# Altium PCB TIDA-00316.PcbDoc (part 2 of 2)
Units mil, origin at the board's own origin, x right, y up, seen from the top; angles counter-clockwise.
Board outline 3345 x 4425 mil, 4 copper layers (Top Layer, L1_GND, L2_POWER, Bottom Layer), stack 90 mil thick; 218 components, 101 nets, 687 pads, 221 vias.

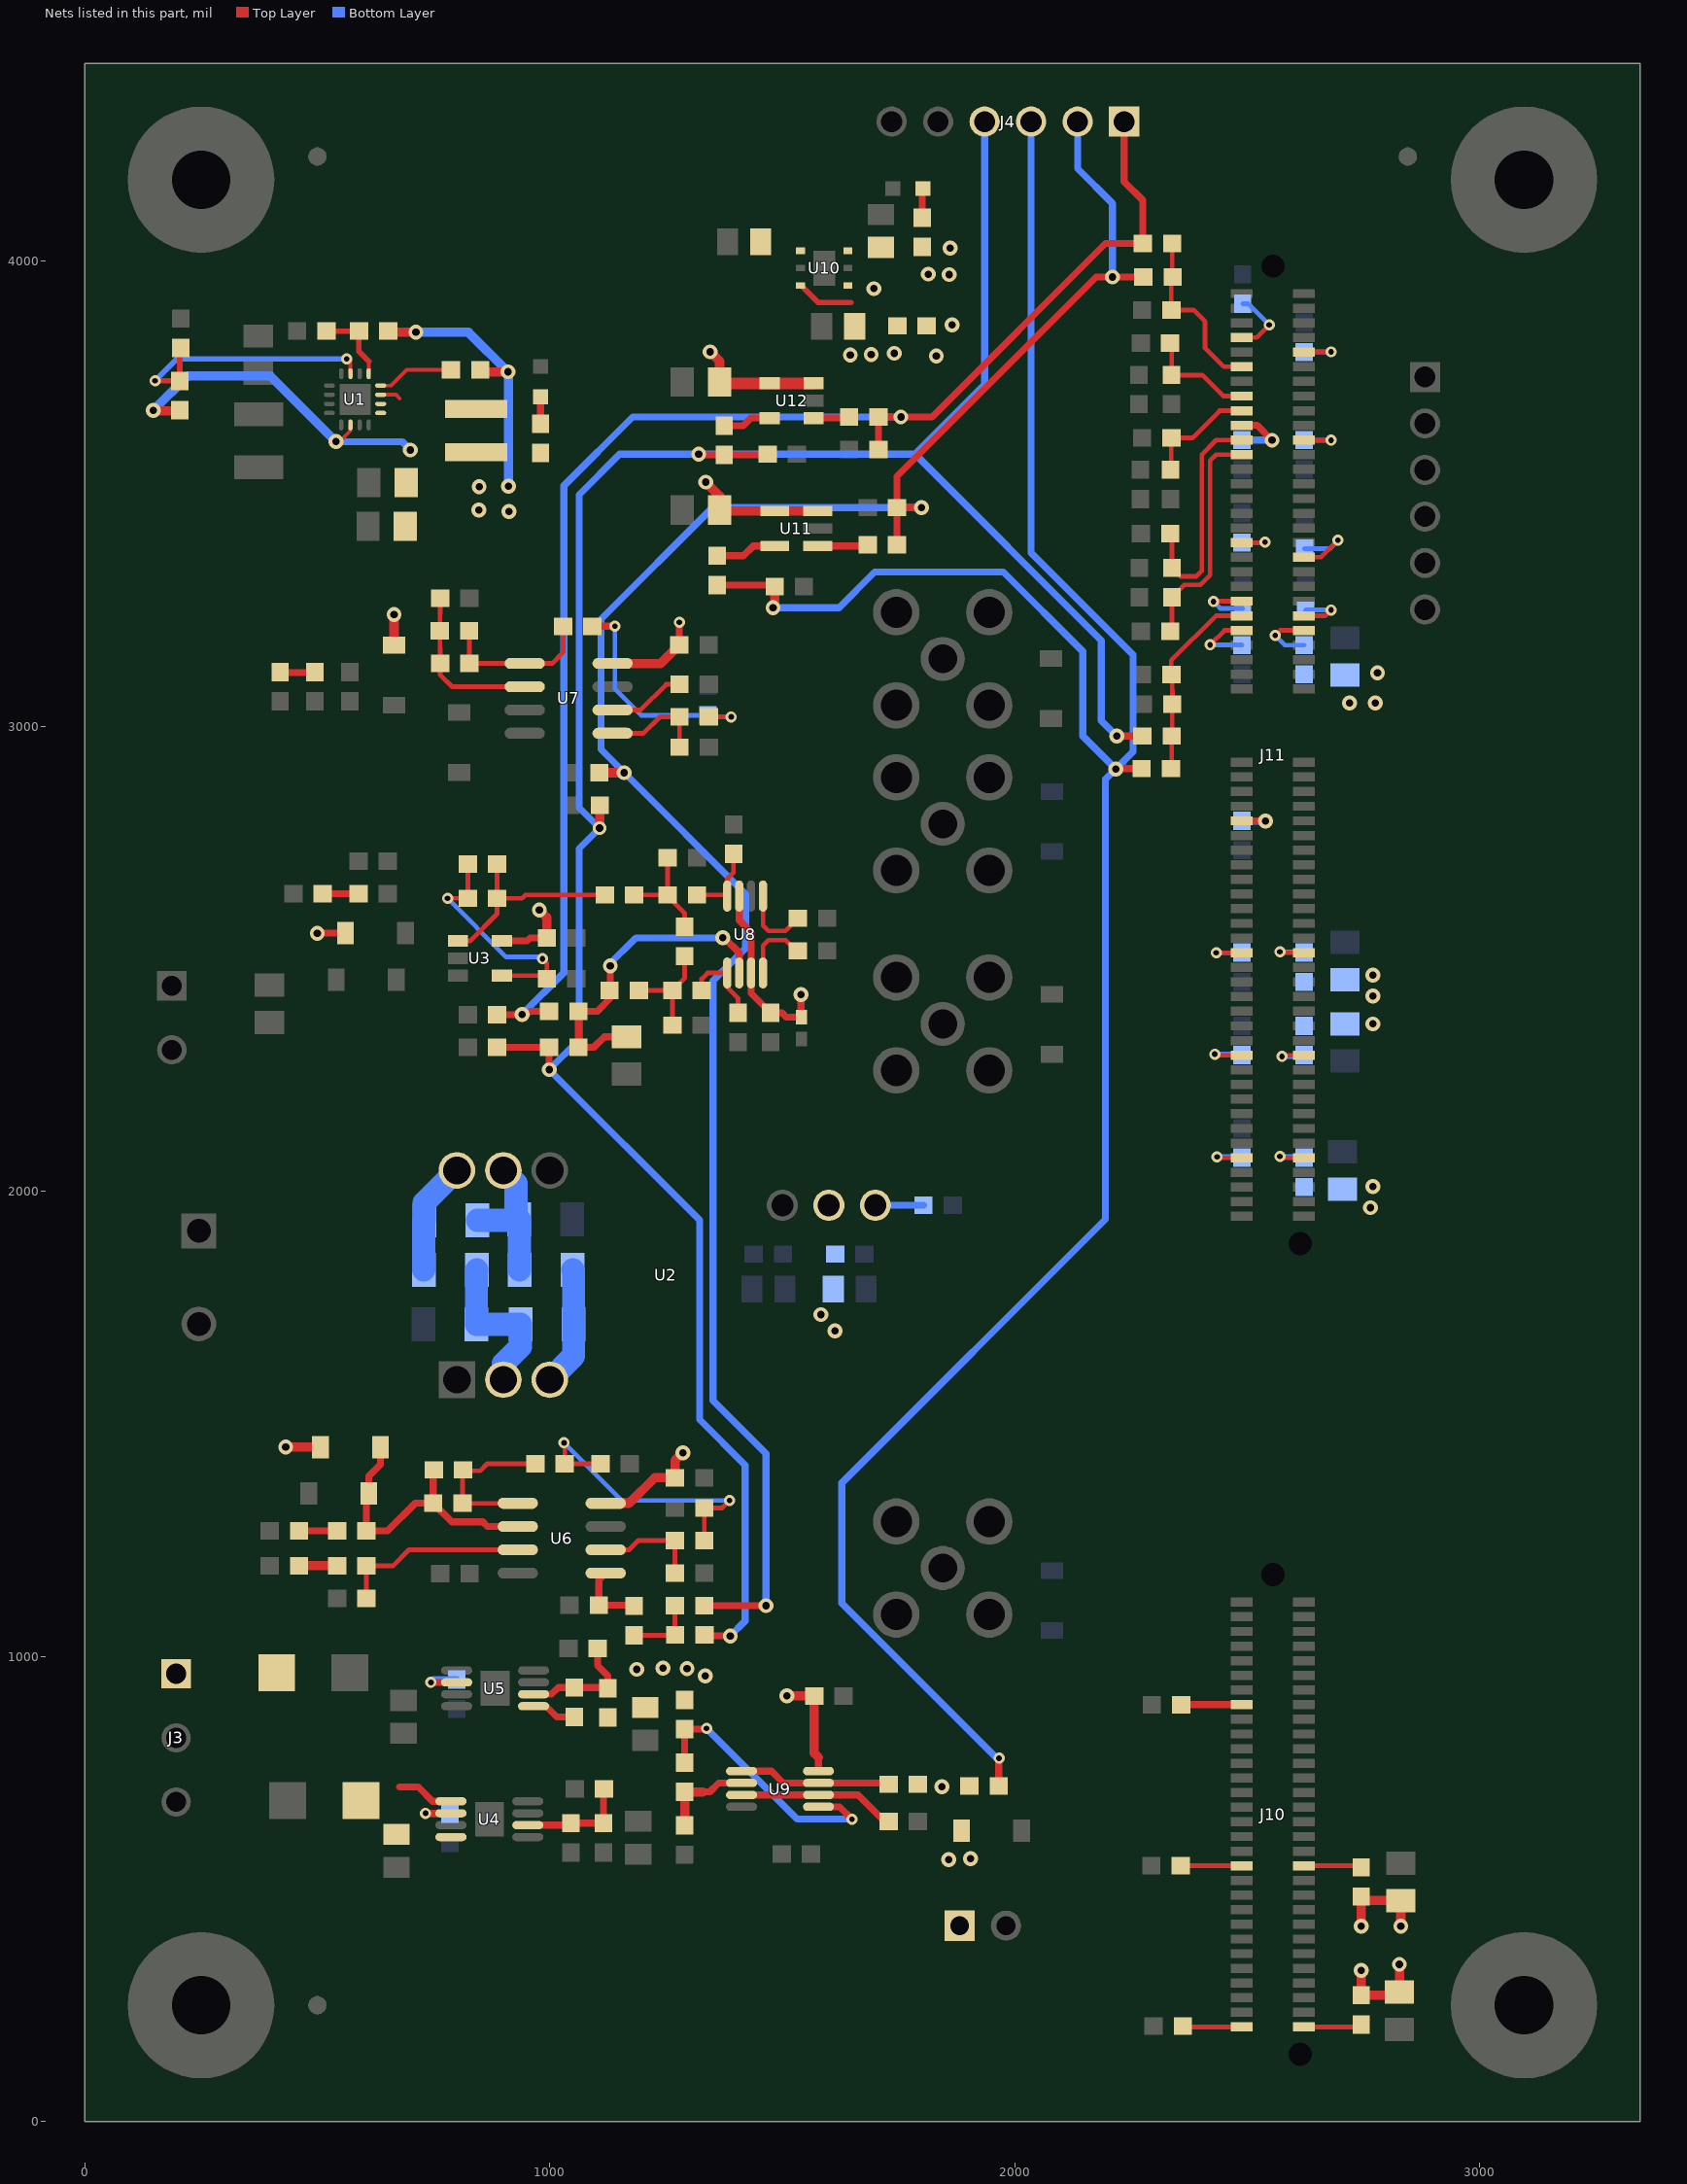
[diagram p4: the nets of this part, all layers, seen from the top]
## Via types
v1: diameter 32, hole 16, Top Layer to Bottom Layer, 160 vias
v2: diameter 24, hole 12, Top Layer to Bottom Layer, 40 vias
v3: diameter 19.68, hole 7.87, Top Layer to Bottom Layer, 16 vias
v4: diameter 30, hole 16, Top Layer to Bottom Layer, 5 vias

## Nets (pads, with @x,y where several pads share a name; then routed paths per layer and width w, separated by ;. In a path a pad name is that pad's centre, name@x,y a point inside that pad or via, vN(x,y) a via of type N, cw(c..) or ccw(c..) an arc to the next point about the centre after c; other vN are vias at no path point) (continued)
NetC5_1: C5.1 R16.1 R22.1 U6.1 | length 352.2
  Top Layer w10: U6.1@931.08,1329.22 R16.1@812.06,1329.22 812.06,1399.22 850.57,1399.22 865.57,1414.22 R22.1@969.07,1414.22
NetC5_2: C5.2 D1.1 D2.2 R10.2 R16.2 U6.2 | length 635
  Top Layer w15: D2.2@635.47,1450 635.47,1412.47 610.47,1387.47 D1.1@610.47,1350 605.5,1345.03 R10.2@605.5,1270 651,1270 710.22,1329.22 R16.2@749.07,1329.22 ; C5.2@749.07,1401 R16.2@749.07,1329.22 ; U6.2@931.08,1279.22 865.57,1279.22 855.57,1289.22 789.07,1289.22 R16.2@749.07,1329.22
NetC6_1: C6.1 D4.2 U4.5 U4.8 | length 123
  Top Layer w15: 677,719 717,719 747.61,688.39 U4.5@787.32,688.39
NetC10_1: C10.1 R18.1 R26.1 U7.1 | length 337.8
  Top Layer w10: C10.1@826.93,3205 R18.1@826.93,3135 U7.1@945.94,3135 1005,3135 1028.5,3158.5 R26.1@1028.5,3215
NetC10_2: C10.2 R17.2 R18.2 U7.2 | length 356.7
  Top Layer w10: R17.2@763.94,3275 C10.2@763.5,3205 R18.2@763.94,3135 763.94,3111.06 790,3085 U7.2@945.94,3085
NetC11_1: C11.1 R19.1 R31.1 U3.1 | length 450.6
  Top Layer w10: U3.1@802.4,2538.4 828.4,2538.4 886.5,2596.5 R19.1@886.5,2630 ; C11.1@886.5,2704 R19.1@886.5,2630 ; R31.1@1118.49,2637.2 947.2,2637.2 940,2630 R19.1@886.5,2630
NetC11_2: C11.2 R19.2 R23.2 U3.4 | length 524.4
  Top Layer w10: v2(780,2630) R19.2@823.5,2630 823.5,2699 818.5,2704 C11.2@818.5,2705 ; U3.4@896.89,2463.6 987.09,2463.6 R23.2@993.49,2457.2 993.49,2490.51 v2(984,2500)
  Bottom Layer w10: v2(780,2630) 906,2504 980,2504 v2(984,2500)
NetC14_1: C14.1 R22.2 R34.1 R35.1 | length 661.1
  Top Layer w10: v2(1030.57,1459.22) 1032.06,1457.72 R22.2@1032.06,1414.22 C14.1@1109.07,1414.22 ; R35.1@1332.06,1249.22 R34.1@1332.06,1319.22 1370.57,1319.22 v2(1386.57,1335.22)
  Bottom Layer w10: v2(1030.57,1459.22) 1154.57,1335.22 v2(1386.57,1335.22)
NetC15_2: C15.2 R28.2 R30.1 U4.2 | length 238.2
  Top Layer w15: U4.2@952.68,637.2 1040.71,637.2 C15.2@1045,641.5 R30.1@1115,641.5 1115,713.5 R28.2@1116.5,715
NetC16_2: C16.2 R29.2 R32.1 U5.2 | length 266.5
  Top Layer w15: U5.2@964.96,918.58 1003.58,918.58 1017.87,932.87 C16.2@1052.28,932.87 1123.62,932.87 R32.1@1118.78,937.72 ; R29.2@1102.78,1017.38 1102.78,980.22 1125,958 R32.1@1125,931.5
NetC19_2: C19.2 R35.2 U6.6 | length 227.3
  Top Layer w10: U6.6@1120.06,1229.22 1170.57,1229.22 1190.57,1249.22 R35.2@1269.07,1249.22 C19.2@1269.07,1179.22
NetC23_1: C23.1 R42.2 U7.5 | length 223.5
  Top Layer w10: U7.5@1134.92,2985 1201.5,2985 1236.5,3020 R42.2@1278.94,3020 C23.1@1278.94,2955
NetC26_1: C26.1 R31.2 R37.1 R38.2 | length 235.6
  Top Layer w10: R31.2@1181.48,2637.2 R38.2@1253.49,2637.2 ; R37.1@1253.49,2717.2 R38.2@1253.49,2637.2 ; C26.1@1289.98,2568.7 1289.98,2597.22 1253.49,2633.71 R38.2@1253.49,2637.2
NetC26_2: C26.2 R33.2 R39.2 R40.1 | length 231.5
  Top Layer w10: R33.2@1191.48,2432.2 R39.2@1263.49,2432.2 ; R40.1@1263.49,2357.2 R39.2@1263.49,2432.2 ; C26.2@1289.98,2505.7 1289.98,2458.7 R39.2@1263.49,2432.2
NetC27_2: C27.2 R38.1 U8.8 | length 162.5
  Top Layer w10: R38.1@1316.48,2637.2 1379.27,2637.2 U8.8@1381.6,2634.88 1381.6,2671.6 1394.98,2684.98 C27.2@1394.98,2725.7
NetC28_2: C28.2 R39.1 U8.1 | length 180.6
  Top Layer w10: R39.1@1326.48,2432.2 1326.48,2456.9 1339.11,2469.52 U8.1@1381.6,2469.52 1381.6,2441.6 1381.6,2438.4 1404.98,2415.02 C28.2@1404.98,2383.7
NetC29_1: C29.1 U10.1
NetC42_1: C42.1 J11.11 R63.2 R64.2 | length 379.4
  Top Layer w10: R63.2@2338.5,4038 2338.5,3966 2336.5,3964 C42.1@2336.5,3895 2384,3895 2409,3870 2409,3813 2449.07,3772.93 J11.11@2488.07,3772.93
NetC43_1: C43.1 C61.1 J11.45 R60.2 R62.2 | length 461.6
  Top Layer w10: R60.2@2335.5,2909 2337.5,2911 R62.2@2337.5,2979 2338.5,2980 C43.1@2338.5,3047 ; 2339,3077 C43.1@2339,3047 ; C43.1@2343,3047 C43.1@2339,3047 ; J11.45@2488.07,3237.5 2432.5,3237.5 2336.5,3141.5 C61.1@2336.5,3111 2338.5,3109 C43.1@2338.5,3047 ; C43.1@2338.5,3047 C43.1@2339,3047 ; C43.1@2338.5,3047 2339,3046.5 C43.1@2339,3047
NetC44_1: C44.1 J11.17 R61.2 | length 244.9
  Top Layer w10: C44.1@2335,3551.5 2336.5,3552.99 R61.2@2336.5,3620 2382,3620 2440.45,3678.44 J11.17@2488.07,3678.44
NetC45_1: C45.1 J11.15 R57.2 | length 239.7
  Top Layer w10: R57.2@2333.7,3824 2337.2,3820.5 C45.1@2337.2,3755.5 2337.7,3755 2403,3755 2448.06,3709.94 J11.15@2488.07,3709.94
NetC46_1: C46.1 J11.21 R58.2 | length 501.2
  Top Layer w10: R58.2@2334.23,3414 2337.73,3410.5 C46.1@2337.73,3340.5 2356.23,3322 2390,3322 2402,3334 2402,3584.45 2433,3615.45 J11.21@2488.07,3615.45
NetC46_2: C46.2 J11.23 R59.2 | length 496.3
  Top Layer w10: R59.2@2334.23,3204 2337.73,3207.5 C46.2@2337.73,3277.5 2364.23,3304 2399,3304 2420,3325 2420,3571 2432.96,3583.96 J11.23@2488.07,3583.96
NetC57_2: C57.2 R26.2 R42.1 | length 506.5
  Top Layer w10: R42.1@1341.93,3020 v2(1390,3020)
  Top Layer w15: R26.2@1091.5,3215 v2(1140,3215)
  Bottom Layer w10: v2(1140,3215) 1140,3079.92 1196.42,3023.5 C57.2@1340,3023.5 1343.5,3020 v2(1390,3020)
NetC58_1: C58.1 U5.6 | length 113.3
  Top Layer w15: v2(744.17,944.17) U5.6@799.61,944.17
  Bottom Layer w15: v2(744.17,944.17) 750.08,950.08 C58.1@799.61,950.08
NetC59_1: C59.1 U4.6 | length 109.9
  Top Layer w15: v2(732.8,662.8) U4.6@787.32,662.8
  Bottom Layer w15: v2(732.8,662.8) 731.5,661.5 C59.1@785,661.5
NetJ10_135: J10.135 R96.2 | length 130.7
  Top Layer w15: R96.2@2357.5,896 2357.72,896.22 J10.135@2488.07,896.22
NetJ10_157: J10.157 R65.2 | length 131.7
  Top Layer w10: R65.2@2356.5,550 2356.73,549.76 J10.157@2488.07,549.76
NetJ10_158: J10.158 R68.1 | length 124.4
  Top Layer w10: J10.158@2621.93,549.76 2741.73,549.76 R68.1@2745,546.5
NetJ10_179: J10.179 R66.2 | length 127.3
  Top Layer w10: R66.2@2361.5,205 2363.19,203.31 J10.179@2488.07,203.31
NetJ10_180: J10.180 R67.1 | length 125.2
  Top Layer w10: J10.180@2621.93,203.31 2739.8,203.31 R67.1@2745,208.5
NetJ11_7: J11.7 R77.1 | length 146
  Top Layer w10: J11.7@2488.07,3835.93 2519.93,3835.93 v2(2547,3863)
  Bottom Layer w10: R77.1@2490,3908.5 2501.5,3908.5 v2(2547,3863)
NetJ11_10: J11.10 R73.2 | length 116.6
  Top Layer w10: J11.10@2621.93,3804.43 2679.43,3804.43 v2(2680,3805)
  Bottom Layer w10: R73.2@2621.93,3804.43 2622.5,3805 v2(2680,3805)
NetJ11_19: J11.19 R97.2 | length 143.3
  Top Layer w15: J11.19@2488.07,3646.95 2521.05,3646.95 v1(2553,3615)
  Bottom Layer w15: R97.2@2488.07,3615.45 2552.55,3615.45 v1(2553,3615)
NetJ11_22: J11.22 R71.2 | length 116.5
  Top Layer w10: J11.22@2621.93,3615.45 2679.55,3615.45 v2(2680,3615)
  Bottom Layer w10: R71.2@2621.93,3615.45 2622.38,3615 v2(2680,3615)
NetJ11_35: J11.35 R81.2 | length 100.7
  Top Layer w10: J11.35@2488.07,3394.98 2536.98,3394.98 v2(2538,3396)
  Bottom Layer w10: R81.2@2488.07,3394.98 2536.98,3394.98 v2(2538,3396)
NetJ11_38: J11.38 R70.2 | length 167.9
  Top Layer w10: J11.38@2621.93,3363.48 2658.48,3363.48 v2(2695,3400)
  Bottom Layer w10: R70.2@2623,3381.5 2676.5,3381.5 v2(2695,3400)
NetJ11_43: J11.43 R78.2 | length 130.5
  Top Layer w10: v2(2427,3268) 2427.99,3268.99 J11.43@2488.07,3268.99
  Bottom Layer w10: v2(2427,3268) 2441.5,3253.5 R78.2@2490,3253.5
NetJ11_46: J11.46 R69.2 | length 118.9
  Top Layer w10: J11.46@2621.93,3237.5 2667.5,3237.5 v2(2680,3250)
  Bottom Layer w10: R69.2@2625,3248.5 2626.5,3250 v2(2680,3250)
NetJ11_47: J11.47 R79.2 | length 149.2
  Top Layer w10: v2(2420,3175) 2451,3206 J11.47@2488.07,3206
  Bottom Layer w10: v2(2420,3175) 2487.58,3175 R79.2@2488.07,3174.51
NetJ11_48: J11.48 R74.1 | length 136.9
  Top Layer w10: v2(2560,3195) 2571,3206 J11.48@2621.93,3206
  Bottom Layer w10: v2(2560,3195) 2580.49,3174.51 R74.1@2621.93,3174.51
NetJ11_65: J11.65 R95.2 | length 101.5
  Top Layer w15: J11.65@2488.07,2796.56 2538.45,2796.56 v1(2539,2796)
  Bottom Layer w15: R95.2@2488.62,2796 v1(2539,2796)
NetJ11_83: J11.83 R80.2 | length 110
  Top Layer w10: v2(2433.09,2513.09) J11.83@2488.07,2513.09
  Bottom Layer w10: v2(2433.09,2513.09) R80.2@2488.07,2513.09
NetJ11_84: J11.84 R75.1 | length 105.4
  Top Layer w10: v2(2570,2515) 2571.91,2513.09 J11.84@2621.93,2513.09
  Bottom Layer w10: v2(2570,2515) 2620.02,2515 R75.1@2621.93,2513.09
NetJ11_97: J11.97 R82.2 | length 118.1
  Top Layer w10: v2(2430,2295) 2432.38,2292.62 J11.97@2488.07,2292.62
  Bottom Layer w10: v2(2430,2295) 2485.69,2295 R82.2@2488.07,2292.62
NetJ11_98: J11.98 R72.1 | length 96.5
  Top Layer w10: v2(2574.77,2290) 2577.38,2292.62 J11.98@2621.93,2292.62
  Bottom Layer w10: v2(2574.77,2290) 2619.31,2290 R72.1@2621.93,2292.62
NetJ11_111: J11.111 R83.2 | length 112.2
  Top Layer w10: v2(2435,2074.29) 2432.86,2072.15 J11.111@2488.07,2072.15
  Bottom Layer w10: v2(2435,2074.29) 2485.93,2074.29 R83.2@2488.07,2072.15
NetJ11_112: J11.112 R76.1 | length 111.9
  Top Layer w10: v2(2570,2075) 2567.14,2072.15 J11.112@2621.93,2072.15
  Bottom Layer w10: v2(2570,2075) 2619.08,2075 R76.1@2621.93,2072.15
NetL1_1: L1.1 U1.1 U1.2 U1.3 | length 44.1
  Top Layer w8: U1.3@636.12,3712.84 669.16,3712.84 677,3705
NetLD1_2: LD1.2 R93.1 | length 58
  Top Layer w15: R93.1@980,3650.5 LD1.2@980,3708.52
NetLD2_2: LD2.2 R55.1 | length 68.1
  Top Layer w15: R55.1@1801,4088.5 1801,4154.52 LD2.2@1802.48,4156
NetR1_1: R1.1 R2.2 U1.7 | length 590.7
  Top Layer w8: v2(563,3790) 566,3790 571.16,3784.84 U1.7@571.16,3758.12
  Top Layer w12: v2(151,3743) 203.5,3743 R1.1@204,3742.5 R2.2@204,3811.5
  Bottom Layer w12: v2(151,3743) 198,3790 v2(563,3790)
NetR3_1: R3.1 R10.1 | length 82
  Top Layer w15: R3.1@460.5,1270 R10.1@542.5,1270
NetR4_1: R4.1 R11.2 | length 82
  Top Layer w20: R4.1@460.5,1195 R11.2@542.5,1195
NetR5_2: R5.2 R13.1 U1.5 | length 170.7
  Top Layer w8: U1.5@610.53,3758.12 610.53,3784.47
  Top Layer w12: R5.2@519.5,3850 520,3849.5 589,3849.5 589,3806 610.53,3784.47
  Top Layer w20: R13.1@589,3849.5 R13.1@589.5,3850
NetR7_1: R7.1 R14.1 | length 74.1
  Top Layer w10: R7.1@420,3116.5 R7.1@421.5,3115
  Top Layer w15: R7.1@421.5,3115 R14.1@493.5,3115
NetR8_1: R8.1 U1.4 | length 165.3
  Top Layer w8: U1.4@636.12,3732.53 658.53,3732.53 692,3766 R8.1@787.5,3766
NetR9_1: R9.1 R15.1 | length 77
  Top Layer w15: R9.1@511.5,2640 R15.1@588.5,2640
NetR11_1: R11.1 R12.1 U6.3 | length 409.8
  Top Layer w10: R12.1@605.5,1125 R11.1@605.5,1195 663,1195 697.22,1229.22 U6.3@931.08,1229.22
NetR36_1: R36.1 R92.1 R94.1 | length 152.1
  Top Layer w10: R94.1@1181,1045.5 1269.01,1045.5 R92.1@1269.5,1046 1269.07,1046.43 R36.1@1269.07,1109.22
NetR41_2: R41.2 U7.6 | length 166.8
  Top Layer w10: U7.6@1134.92,3035 1195.36,3035 1250.36,3090 R41.2@1278.94,3090
NetR43_1: R43.1 R44.2 U9.5 | length 599.7
  Top Layer w15: R44.2@1290,771.5 R43.1@1290,843.5 1338.5,843.5 v2(1337.01,845) ; U9.5@1577.68,676.61 1623.39,676.61 v2(1650,650)
  Bottom Layer w15: v2(1337.01,845) 1532.01,650 v2(1650,650)
NetR44_1: R44.1 R45.2 U9.2 | length 202.3
  Top Layer w15: 1328.5,708.5 1343.5,708.5 1362.8,727.8 U9.2@1412.32,727.8
  Top Layer w20: R45.2@1290,636.5 R44.1@1290,708.5 1328.5,708.5
NetR46_2: R46.2 U11.5 | length 132.7
  Top Layer w15: R46.2@1360,3366.5 1416.5,3366.5 1437.6,3387.6 U11.5@1484,3387.6
NetR47_2: R47.2 U12.5 | length 104.4
  Top Layer w15: R47.2@1375,3646.5 1416.5,3646.5 1432.6,3662.6 U12.5@1472.76,3662.6
NetR48_2: R48.2 U8.5 | length 154.5
  Top Layer w10: U8.5@1458.37,2634.88 1458.37,2571.63 1470.07,2559.93 1506.22,2559.93 R48.2@1533.49,2587.2
NetR49_2: R49.2 U8.4 | length 148.2
  Top Layer w10: U8.4@1458.37,2469.52 1458.37,2528.37 1470,2540 1506.93,2540 1529.73,2517.2 R49.2@1533.49,2517.2
NetR50_2: R50.2 U12.1 | length 77.3
  Top Layer w15: U12.1@1567.24,3662.6 1641.1,3662.6 R50.2@1643.5,3665
NetR51_2: R51.2 U11.1 | length 108.5
  Top Layer w15: U11.1@1576,3387.6 1681.1,3387.6 R51.2@1683.5,3390
NetR52_1: R52.1 U9.1 U9.7 | length 327.9
  Top Layer w15: U9.1@1412.32,753.39 1476.61,753.39 1502.2,727.8 U9.7@1577.68,727.8 1725.71,727.8 R52.1@1728.5,725
NetR53_1: R53.1 R94.2 U6.5 | length 151.4
  Top Layer w15: U6.5@1120.06,1179.22 1105.5,1164.66 R53.1@1105.5,1110 1179.5,1110 R94.2@1181,1108.5
NetR84_1: R84.1 U2.9 | length 103.5
  Bottom Layer w15: U2.9@1700,1970 R84.1@1803.5,1970
NetR85_1: R85.1 R87.2 U2.3 | length 258
  Bottom Layer w50: U2.3@1000,1595 1051.09,1646.09 R87.2@1051.09,1714 1051.09,1829 R85.1@1049.09,1831
NetR85_2: R85.2 R86.2 R89.1 U2.5 | length 319.1
  Bottom Layer w50: R89.1@844.09,1938 931.91,1938 R86.2@933.91,1940 ; U2.5@900,2045 927.63,2017.37 927.63,1946.28 R86.2@933.91,1940 ; R85.2@934.91,1831 934.91,1939 R86.2@933.91,1940
NetR87_1: R87.1 R88.2 R90.1 U2.2 | length 346.5
  Bottom Layer w50: R90.1@843.09,1831 842.09,1830 R88.2@842.09,1714 R87.1@936.91,1714 936.91,1665.91 900,1629 U2.2@900,1595
NetR89_2: R89.2 R90.2 U2.6 | length 243.4
  Bottom Layer w50: R90.2@728.91,1831 728.91,1937 R89.2@729.91,1938 729.91,1974.91 U2.6@800,2045
NetR?_2: R?.2 U9.3 U9.6 | length 339.9
  Top Layer w15: U9.3@1412.32,702.2 U9.6@1577.68,702.2 1662.8,702.2 R?.2@1720,645
  Top Layer w20: R?.2@1720,645 R?.2@1728.5,645
OC_FAULT: D9.1 J9.1 R52.2 R56.1 | length 2
  Top Layer w15: v1(1858,563) v1@1858,565
  other v1: 1905,565 1843,720
P5V: C13.1 C22.1 C24.1 C25.1 C31.1 C38.1 C60.1 D2.1 D6.1 D7.1 R54.1 R55.2 U3.5 U7.8 U8.3 U8.7 U10.6 U11.3 U11.4 U12.3 U12.4 | length 1534.1
  Top Layer w15: v1(500,2555) D6.1@560.53,2555 ; U3.5@896.89,2538.4 951.4,2538.4 958,2545 C13.1@993.5,2545 ; C22.1@1278.5,3175 v2(1278.5,3223.5) ; C25.1@1360,3460 C25.1@1362.4,3462.4 ; C24.1@1370,3740 C24.1@1372.6,3737.4 ; U8.7@1407.19,2634.88 1407.19,2582.81 1432.78,2557.22 U8.3@1432.78,2469.52 1432.78,2425.9 C31.1@1474.98,2383.7 1499.3,2383.7 1508.38,2374.62 C60.1@1541,2374.62 1540,2375.62 v1(1540,2423)
  Top Layer w20: v1(432,1450) D2.1@506.53,1450 ; D7.1@665,3174.47 v1(665,3240) ; v1(977.5,2605) 993.5,2589 C13.1@993.5,2545 ; U7.8@1134.92,3135 1238.5,3135 C22.1@1278.5,3175 ; v1(1335,3525) 1365,3495 C25.1@1365,3465 ; v1(1345,3805) 1365,3785 C24.1@1365,3740 ; C25.1@1362.4,3462.4 U11.4@1484,3462.4 U11.3@1576,3462.4
  Top Layer w25: C24.1@1372.6,3737.4 U12.4@1472.76,3737.4 U12.3@1567.24,3737.4
  other v1: 1831,3796 1865,3863 1859,3971 1814,3972 1861,4028
P12V: C16.1 C18.1 C21.1 C34.1 C53.1 C54.1 R32.2 R43.2 U2.8 U5.1 U6.8 U9.8 | length 561.4
  Top Layer w10: v1@1195,975 v1@1198,975
  Top Layer w15: U5.1@964.96,892.99 992.01,892.99 1015.12,869.88 C16.1@1052.28,869.88 ; U9.8@1577.68,753.39 1577.68,782.68
  Top Layer w20: U6.8@1120.06,1329.22 1170.57,1329.22 1225.57,1384.22 C18.1@1269.07,1384.22 1269.07,1421.07 v1(1286,1438) ; v1(1510,915) C34.1@1568.5,915 1568.5,791.85 1577.68,782.68
  Bottom Layer w15: v1(1583,1735) v1@1583,1740
  other v1: 1334,958 1187,972 1295,974 1243,975 1613,1700
P15V: D3.2 J3.1
PVMID: C9.1 C12.1 C36.1 C47.1 C48.1 C49.1 C50.1 C51.1 C52.1 L1.2 R1.2 R8.2 R13.2 R54.2 R67.2 R68.2 R72.2 R74.2 R75.2 R76.2 R93.2 U1.14 U10.3 U10.4 | length 1891.5
  Top Layer w8: v1(540,3612) 548,3612 571.16,3635.16 U1.14@571.16,3647.88
  Top Layer w12: U10.3@1539.02,3947.6 1540.4,3947.6 1577,3911 1647,3911
  Top Layer w20: v1(147,3679) 147,3678 202.5,3678 R1.2@204,3679.5 ; R13.2@652.5,3850 655.5,3847 v1(712,3847) ; R8.2@850.5,3766 854.5,3762 v1(910,3762) ; v1(2745,325) R67.2@2745,271.5 2820.5,271.5 C47.1@2827,278 v1(2827,338) ; v1(2745,420) R68.2@2745,483.5 2753.5,475 C48.1@2830,475 v1(2830,420)
  Bottom Layer w15: v1(540,3612) 682,3612 v1(700,3594)
  Bottom Layer w20: v1(147,3679) 221,3753 399,3753 v1(540,3612) ; v1(712,3847) 825,3847 v1(910,3762) 911,3761 v1(911,3516)
  other v1: 2765,1965 2770,2010 2770,2360 2770,2420 2770,2465 2720,3050 2775,3050 2780,3115 912,3462 847,3465 848,3515 1646,3798 1691,3799 1741,3802 1697,3941
REF2025_REF: C30.1 J4.4 R21.1 R25.2 R47.1 R62.1 R91.1 R92.2 | length 5504.4
  Top Layer w15: R21.1@886.5,2310 R25.2@998.5,2310 v1(998.5,2261.5) ; v1(1320,3585) 1321.5,3583.5 R47.1@1375,3583.5 1467.01,3583.5 C30.1@1468.5,3585 ; R92.2@1332.5,1044 v1(1388,1044) ; v1(2219,2979) 2226,2979 2227,2980 2228,2979 R62.1@2274.5,2979
  Top Layer w20: v4(1107,2781.01) 1107.5,2781.5 R91.1@1107.5,2830
  Bottom Layer w15: v1(1388,1044) 1420,1076 1420,1411 1322,1509 1322,1938 v1(998.5,2261.5) 1063,2325.99 1063,2737.01 v4(1107,2781.01) 1063,2825.01 1063,3498 1150,3585 v1(1320,3585) 1785.53,3585 ; J4.4@1935,4300 1935,3734.47 1785.53,3585 ; v1@2217.5,2970.5 v1@2222.5,2975.5 ; v1(2219,2979) 2186,3012 2186,3184.53 1785.53,3585
REF2025_REF/2: C35.1 J4.1 R20.1 R24.2 R50.1 R63.1 | length 3147.8
  Top Layer w15: R20.1@886.5,2380 v1(940,2380) 950,2380 957.2,2387.2 R24.2@998.49,2387.2 ; C35.1@1706.5,3595 R50.1@1706.5,3665 v1(1755,3665) 1822,3665 2195,4038 R63.1@2275.5,4038 2275.5,4130.5 2235,4171 J4.1@2235,4300
  Bottom Layer w15: v1(940,2380) 1030,2470 1030,3517 1178,3665 v1(1755,3665)
REF2033_REF: C32.1 J4.3 R46.1 R56.2 R60.1 | length 5350.8
  Top Layer w15: R46.1@1360,3303.5 1480,3303.5 C32.1@1483.5,3300 ; R56.2@1965.5,721 1965.5,780.5 v2(1966,781) ; v1(2217,2908) 2223,2908 2225,2910 2226,2909 R60.1@2272.5,2909
  Top Layer w20: v1(1480,3255) 1483.5,3258.5 C32.1@1483.5,3300
  Bottom Layer w15: v1(1480,3255) 1622,3255 1698.5,3331.5 1975.5,3331.5 2146,3161 2146,2979 v1(2217,2908) ; v2(1966,781) 1961.37,781 1628,1114.37 1628,1373 2195,1940 2195,2886 v1(2217,2908) ; J4.3@2035,4300 2035,3373 2254,3154 2254,2945 v1(2217,2908)
REF2033_REF/2: C37.1 J4.2 R27.1 R36.2 R51.1 R64.1 | length 4573.5
  Top Layer w15: R36.2@1332.06,1109.22 1464.78,1109.22 v1(1465,1109) ; R51.1@1746.5,3390 C37.1@1746.5,3470 ; v1(1799,3470) C37.1@1746.5,3470 ; R64.1@2276.5,3966 v1(2210,3966) 2175,3966 1746.5,3537.5 C37.1@1746.5,3470
  Top Layer w20: R27.1@1106.5,2900 v1(1160,2900)
  Bottom Layer w15: v1(1465,1109) 1465,1436 1351,1550 1351,2453 1421,2523 1421,2639 v1(1160,2900) 1110,2950 1110,3230 1350,3470 v1(1799,3470) ; J4.2@2135,4300 2135,4199 2210,4124 v1(2210,3966)
VOCM: C17.1 R24.1 R25.1 R33.1 U8.2 | length 708.6
  Top Layer w15: v1(1130,2485) 1130,2415 1102.2,2387.2 R24.1@1061.48,2387.2 R25.1@1061.5,2310 1095,2310 1117.2,2332.2 C17.1@1164.98,2332.2 ; v1(1372,2545) 1375,2545 1407.19,2512.81 U8.2@1407.19,2469.52
  Bottom Layer w15: v1(1130,2485) 1125,2485 1185,2545 v1(1372,2545)
pads on no net: FID1.1 FID2.1 FID3.1 FID4.1 FID5.1 FID6.1 H1.1 H2.1 H3.1 H4.1 H9.0 H10.0 H11.0 H12.0 J10.121 J10.122 J10.123 J10.124 J10.125 J10.126 J10.127 J10.128 J10.129 J10.130 J10.131 J10.132 J10.133 J10.134 J10.136 J10.137 J10.138 J10.139 J10.140 J10.141 J10.142 J10.143 J10.144 J10.145 J10.146 J10.147 J10.148 J10.149 J10.150 J10.151 J10.152 J10.153 J10.154 J10.155 J10.156 J10.159 J10.160 J10.161 J10.162 J10.163 J10.164 J10.165 J10.166 J10.167 J10.168 J10.169 J10.170 J10.171 J10.172 J10.173 J10.174 J10.175 J10.176 J10.177 J10.178 J10.181 J10.182 J11.1 J11.2 J11.3 J11.4 J11.5 J11.6 J11.8 J11.9 J11.12 J11.13 J11.14 J11.16 J11.18 J11.20 J11.24 J11.25 J11.26 J11.27 J11.28 J11.29 J11.30 J11.31 J11.32 J11.33 J11.34 J11.36 J11.37 J11.39 J11.40 J11.41 J11.42 J11.44 J11.49 J11.50 J11.51 J11.52 J11.53 J11.54 J11.55 J11.56 J11.57 J11.58 J11.59 J11.60 J11.61 J11.62 J11.63 J11.64 J11.66 J11.67 J11.68 J11.69 J11.70 J11.71 J11.72 J11.73 J11.74 J11.75 J11.76 J11.77 J11.78 J11.79 J11.80 J11.81 J11.82 J11.85 J11.86 J11.87 J11.88 J11.89 J11.90 J11.91 J11.92 J11.93 J11.94 J11.95 J11.96 J11.99 J11.100 J11.101 J11.102 J11.103 J11.104 J11.105 J11.106 J11.107 J11.108 J11.109 J11.110 J11.113 J11.114 J11.115 J11.116 J11.117 J11.118 J11.119 J11.120 J11.121 J11.122 U4.3 U4.7 U5.3 U5.7 U10.5
copper on no net: | length 6498
  Top Layer w8: 2990,1266.7 3090,1266.7 ; 2990,1366.7 3090,1366.7 ; 2990,1466.7 3090,1466.7 ; 2990,1166.7 3090,1166.7 3090,1566.7 2990,1566.7 2990,1166.7
  L1_GND w8: 2990,1166.7 2990,1566.7 ; 2990,1166.7 3090,1166.7 ; 2990,1166.7 3090,1166.7 ; 2990,1166.7 2990,1566.7 ; 2990,1566.7 3090,1566.7 ; 2990,1566.7 3090,1566.7 ; 3090,1166.7 3090,1566.7 ; 3090,1166.7 3090,1566.7 ; 2990,1266.7 3090,1266.7 2990,1266.7 ; 2990,1366.7 3090,1366.7 2990,1366.7 ; 2990,1466.7 3090,1466.7 2990,1466.7
  L2_POWER w8: 2990,1266.7 3090,1266.7 ; 2990,1366.7 3090,1366.7 ; 2990,1466.7 3088,1466.7 ; 2990,1166.7 2990,1566.7 3090,1566.7 3090,1166.7 2990,1166.7
  Bottom Layer w8: 2990,1266.7 3090,1266.7 ; 2990,1366.7 3090,1366.7 ; 2990,1466.7 3090,1466.7 ; 2990,1166.7 2990,1566.7 3090,1566.7 3090,1166.7 2990,1166.7

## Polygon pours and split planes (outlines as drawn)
GND on Top Layer "Bottom-No Net 2" (solid, pour order 58): 484,3884 484,3819 474,3809 290,3809 252,3847 162,3847 154,3855 150,3859 150,3935 150,3945 166,3961 471,3961 484,3948
OC_FAULT on Top Layer "Top Layer-No Net" (solid, remove dead copper, pour order 44): 1900,760 1926,734 1926,400 1911,385 1847,385 1838,394 1838,675 1833,680 1775,680 1770,685 1770,755 1775,760
P5V on Top Layer "Top Layer-No Net" (solid, pour order 52): 1639.89,4053 1630,4043.11 1630,4012 1635,4007 1779,4007 1791,3995 1791,3779 1796,3774 1877,3774 1886,3783 1886,4040 1873,4053
PVMID on Top Layer "Top Layer-No Net" (solid, pour order 50): 1629,3962 1758,3962 1769,3951 1769,3782 1760,3773 1637,3773 1629,3781
NetC29_1 on Top Layer "Top Layer-No Net" (solid, pour order 46): 1546,4009 1550,4013 1550,4076 1545,4081 1430,4081 1424,4075 1424,4017 1432,4009
P12V on Top Layer "Top Layer-No Net 1" (solid, pour order 43): 1130,890 1025,890 1020,885 1020,835 1025,830 1144.57,830 1173.5,858.94 1179.57,865 1230,865 1235,865 1250,880 1580,880 1590,890 1590,995 1580,1005 1180,1005 1165,990 1165,900 1155,890
NetC6_1 on Top Layer "Top Layer-No Net 1" (solid, remove dead copper, pour order 37): 762,621 820,621 824,617 824,595 822,593 535,593 521,607 521,745 530,754 605,754 693,754 705,742 705,631 715,621 739,621
NetC1_1 on Top Layer "Top Layer-No Net 1" (solid, pour order 40): 720,902 828,902 835,895 835,878 832,875 515,875 505,885 505,1005 520,1020 705,1020 715,1010 715,907
NetC3_1 on Top Layer "Top Layer-No Net" (solid, remove dead copper, pour order 51): 570,3075 840,3075 860,3055 860,3000 845,2985 490,2985 475,3000 475,3065 485,3075
P15V on Top Layer "Top Layer-No Net" (solid, remove dead copper, pour order 30): 145,1065 460,1065 480,1045 480,905 460,885 145,885 120,910 120,1040 145,1065
N15V on Top Layer "Top Layer-No Net" (solid, remove dead copper, pour order 33): 155,770 465,770 495,740 495,615 470,590 150,590 125,615 125,740
N12V on Top Layer "Top Layer-No Net" (solid, remove dead copper, pour order 48): 1005,595 1520,595 1520,465 1505,450 1015,450 1000,465 1000,590
NetC4_1 on Top Layer "Top Layer-No Net" (solid, remove dead copper, pour order 49): 630,2748.21 630,2368.21 640,2358.21 705,2358.21 710,2353.21 710,2285 720,2275 840,2275 845,2280 845,2415 840,2420 715,2420 710,2425 710,2753.21 695,2768.21 650,2768.21
NetL1_1 on Top Layer "Bottom-No Net 2" (solid, pour order 39): 626,3720 623,3717 623,3664 633,3654 910,3654 915,3659 915,3718 913,3720
PVMID on Top Layer "Bottom-No Net 2" (solid, pour order 42): 757,3614 1012,3614 1021,3605 1021,3384 1011,3374 669,3374 658,3385 658,3596 676,3614
GND on Top Layer "Bottom-No Net 2" (solid, remove dead copper, pour order 45): 633,3582 635,3580 635,3382 628,3375 282,3375 270,3387 270,3569 283,3582
GND on Top Layer "Top Layer-No Net" (solid, pour order 32): 547,3740 613,3740 616,3737 616,3580 610.53,3574.53 588.47,3574.53 583,3580 583,3668 581,3670 549,3670 547,3672 547,3741
NetC1_1 on Top Layer "Bottom-No Net 2" (solid, remove dead copper, pour order 36): 538,3701 540,3699 540,3662 501,3623 280,3623 272,3631 272,3710 280,3714 477,3714 490,3701
PVMID on Bottom Layer "Top Layer-No Net" (solid, pour order 38): 2595,2030 2590,2025 2590,1955 2595,1950 2790,1950 2795,1955 2795,2020 2785,2030
PVMID on Bottom Layer "Top Layer-No Net" (solid, pour order 34): 2680,2480 2590,2480 2585,2475 2585,2340 2590,2335 2810,2335 2820,2345 2820,2470 2810,2480
PVMID on Bottom Layer "Top Layer-No Net" (solid, pour order 31): 2590,3140 2755,3140 2785,3140 2805,3120 2805,3040 2790,3025 2595,3025 2585,3035 2585,3135 2590,3140
P12V on Bottom Layer "Top Layer-No Net" (hatched 90Degree grid 5 track 8, remove dead copper, pour order 47): 1565,2015 1565,1695 1575,1685 1625,1685 1635,1695 1635,2025 1630,2030 1580,2030
N12V on Bottom Layer "Top Layer-No Net" (hatched 90Degree grid 5 track 8, remove dead copper, pour order 41): 1535,2025 1545,2015 1545,1695 1535,1685 1490,1685 1480,1695 1480,1935 1465,1950 1465,2010 1480,2025
NetC1_1 on Bottom Layer "Top Layer-No Net" (solid, pour order 35): 249,3719 328,3719 340,3707 340,3605 337,3602 248,3602 241,3609 241,3711 249,3719
GND on L1_GND "Top Layer-No Net" (solid, remove dead copper, pour order 53): 110,4360 3220,4360 3260,4320 3260,140 3210,90 145,90 85,150 85,4335
PVMID on L2_POWER "Top Layer-No Net" (solid, pour order 57): 374,3505 374,3359 415,3318 1198,3318 1250,3370 1250,3834 1281,3865 1476,3865 1568,3773 1760,3773 1769,3782 1769,3966 1715,4020 1713,4021.69 1713,4202 1726,4215 2039,4215 2243,4011 2243,246 2310,179 2842,179 2885,222 2885,4018 2541,4362 674,4362 634,4322 634,4195 371,3932 371,3498
P12V on L2_POWER "Top Layer-No Net" (solid, remove dead copper, pour order 55): 1568,2123 1580,2135 2054,2135 2111,2078 2111,774 2057,720 1265,720 1259,726 1259,1440 1289,1470 1500,1470 1570,1540 1570,1620
N12V on L2_POWER "Top Layer-No Net" (solid, remove dead copper, pour order 54): 1545,2120 1530,2135 1300,2135 1240,2075 1240,1585 1190,1535 1090,1535 1060,1505 1060,1435 1035,1410 735,1410 700,1375 700,415 725,390 1515,390 1535,410 1535,640 1505,670 1225,670 1215,680 1215,1400.77 1215,1445 1260,1490 1475,1490 1545,1560
P5V on L2_POWER "Top Layer-No Net" (solid, pour order 56): 1800,4175 1881,4175 2146,3910 2146,2225 2089,2168 633,2168 600,2135 600,1435 590,1425 318,1425 302,1441 302,3196 369,3263 1279,3263 1307,3291 1304,3294 1304,3805 1322,3823 1460,3823 1540,3743 1777,3743 1791,3757 1791,4166

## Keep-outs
L1_GND:
  circle w10: c187,2441.9 r69.56
  circle w10: c245,1915 r69.56
Keep-Out Layer:
  lines w6: 50,50 50,4375 3295,4375 3295,50 50,50
  text ".Layer_Name" at -83,-1959.49 h60
Multi-Layer:
  circle w6: c2845,4225 r46.57
  circle w6: c500,250 r46.57
  circle w6: c500,4225 r46.57

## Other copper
Top Layer:
  text "1" at 3065,1206.7 h40 r90
  text ".layer_Name" at -68,-1949 h60
L1_GND:
  pour cut-out: 1412,2747 1412,2705 1406,2699 1406,2697 1397,2686 1397,2674 1391,2668 1391,2604 1385,2596 1294,2596 1284,2606 1284,2657 1290,2663 1351,2663 1361,2673 1361,2747
  pour cut-out: 1432.18,2412.18 1432.18,2363.18 1428,2359 1383,2359 1378,2364 1378,2401 1370,2409 1304,2409 1300,2413 1300,2450 1326,2476 1360,2476 1365,2481 1365,2495 1374.8,2504.8 1393.09,2504.8 1395,2502.89 1395,2439 1421.82,2412.18
  pour cut-out: 1450,2433 1466,2433 1469,2436 1469,2488 1475,2494 1554,2494 1558,2498 1558,2541 1554,2545 1452,2545 1448,2541 1448,2435
  pour cut-out: 1450,2668.73 1467.27,2668.73 1470,2666 1470,2614 1473,2611 1555,2611 1558,2608 1558,2557 1555,2554 1455,2554 1449,2560 1449,2667.73
  pour cut-out: 615,2113.9 1201.1,2113.9 1225,2090 1225,1525 1200,1500 620,1500 600,1520 600,2098.9
  text "2" at 3059,1305 h40 r90
  text "L1_GND" at -60,-1933 h40
L2_POWER:
  pour cut-out: 1416,2750 1416,2708 1410,2702 1410,2700 1401,2689 1401,2677 1395,2671 1395,2607 1389,2599 1298,2599 1288,2609 1288,2660 1294,2666 1355,2666 1365,2676 1365,2750
  pour cut-out: 1432.18,2412.18 1432.18,2363.18 1428,2359 1383,2359 1378,2364 1378,2401 1370,2409 1304,2409 1300,2413 1300,2450 1326,2476 1360,2476 1365,2481 1365,2495 1374.8,2504.8 1393.09,2504.8 1395,2502.89 1395,2439 1421.82,2412.18
  pour cut-out: 1450,2433 1466,2433 1469,2436 1469,2488 1475,2494 1554,2494 1558,2498 1558,2541 1554,2545 1452,2545 1448,2541 1448,2435
  pour cut-out: 1450,2668.73 1467.27,2668.73 1470,2666 1470,2614 1473,2611 1555,2611 1558,2608 1558,2557 1555,2554 1455,2554 1449,2560 1449,2667.73
  pour cut-out: 615,2113.9 1201.1,2113.9 1225,2090 1225,1525 1200,1500 620,1500 600,1520 600,2098.9
  text "3" at 3059,1406 h40 r90
  text "L2_POWER" at -60,-1953 h40
Bottom Layer:
  text "4" at 3066,1533.7 h40 r90
  text ".Layer_Name" at -9,-1959 h60

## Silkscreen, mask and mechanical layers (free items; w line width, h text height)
Top Overlay:
  drawing of 169 lines, arcs and shapes, not listed
  text "AINP_1" at 2971,3736 h40
  text "AINP_2" at 2973,3645 h40
  text "AINP_D" at 2977,3544 h40
  text "AINM_D" at 2977,3444 h40
  text "GND" at 2977,3333 h40
  text "GND" at 2955,3229 h40
  text "A" at 236,1544 h40
  text "+15V" at 220,1057 h40
  text "-15V" at 228,554 h40
  text "TIDA-00316_E2" at 1046,167 h60
  text "OC FAULT" at 1897,56 h40 r90
  text ".layer_Name" at -42,-1947 h60
Bottom Overlay:
  lines w6: 1736,4242 1736,4259 ; 1837,4241 1837,4261 ; 1938,4233 1938,4260 ; 2036,4234 2036,4261 ; 2136,4239 2136,4260 ; 2252,4241 2252,4262 ; 2417,3305 2455,3305 ; 2547,2228 2558,2228 2583,2253 2583,2255 ; 2659,3281 2700,3281
  text "GND" at 1726,4122 h40 r270
  text "GND" at 1818,4122 h40 r270
  text "REF2033_REF" at 2019,3802 h40 r270
  text "REF2025_REF" at 1920,3799 h40 r270
  text "REF2025_REF/2" at 2239,3728 h40 r270
  text "REF2033_REF/2" at 2124,3722 h40 r270
  text ".Layer_Name" at -83,-1959.49 h60
Top Paste:
  text ".Layer_Name" at -95,-1962.49 h60
Bottom Paste:
  text ".Layer_Name" at -95,-1962.49 h60
Top Solder:
  text ".Layer_Name" at -67,-1970 h60
Bottom Solder:
  text ".Layer_Name" at -20,-1966 h60
M1 Board Outline:
  the board outline again, w10
M2 Board Dimensions:
  rectangle: -65.5,-1106 309.5,-981
  rectangle: -190.5,-981 -65.5,-856
  lines w7: -190.5,-981 809.5,-981 ; -65.5,-1106 -65.5,-856 ; 59.5,-1106 59.5,-856 ; 309.5,-1106 309.5,-856 ; 559.5,-1106 559.5,-856 ; -190.5,-1106 -190.5,-856 809.5,-856 809.5,-1106 -190.5,-1106
  lines w10: -190.5,-1171 -190.5,-1151 ; -130.5,-1181 -190.5,-1161 ; -130.5,-1141 -190.5,-1161 ; 33.58,-1161 -190.5,-1161 ; 585.42,-1161 809.5,-1161 ; 749.5,-1181 809.5,-1161 ; 749.5,-1141 809.5,-1161 ; 809.5,-1171 809.5,-1151
  text "1000 (mil)" at 43.58,-1196.99 h60
M3 3D STEP Top:
  text ".Layer_Name" at -83,-1959.49 h60
M4 3D STEP Bottom:
  text ".Layer_Name" at -83,-1959.49 h60
M5 Assembly Top:
  circle w10: c1845,1190 r31.62
  circle w10: c1850,2360 r31.62
  circle w10: c1845,2790 r29.15
  circle w10: c1845,3145 r28.28
  circle w6: c795.15,1505 r9.85
  circle w6: c194.88,1058 r16.12
  circle w6: c184,2534 r12
  circle w6: c1600,3389 r7.81
  circle w10: c1567.24,3662.6 r7.61
  circle w10: c2234,4224 r13.34
  circle w10: c2791,3761 r18.11
  lines w6: 968,3845 982,3845 ; 981,3808 981,3829 ; 982,3863 982,3845 ; 995,3845 982,3845 ; 1743,4202 1761,4202 1777,4218 1777,4203 ; 1761,4190 1761,4206 ; 1761,4218 1761,4206 ; 1798,4203 1777,4203 ; 982,3845 966,3829 978,3829 990,3829 998,3829 982,3845 ; 1761,4206 1777,4190 1777,4203
  lines w10: -952,-2031.17 5648,-2031.17 ; -952,-1827.83 5650,-1827.83 ; -952,-1624.5 -952,-2234.5 3053,-2234.5 5650,-2234.5 5650,-1624.5 -951.5,-1624.5 -951.5,-2234.5 ; 1513,-2234.5 1513,-1624.5 ; 2780,-1827.83 2780,-1624.5 ; 3620,-1827.83 3620,-1624.5 ; 4242,-2241 4242,-2038.17
  text "H1" at 220,4250 h30
  text "J11" at 2510,4132 h30
  text "2" at 2652,3924 h30
  text "1" at 2436,3920 h30
  text "120" at 2706.81,1900 h30
  text "119" at 2305,1896 h30
  text "J12" at 2513,1266 h30
  text "122" at 2720,1105 h30
  text "121" at 2315,1095 h30
  text "180" at 2715,120 h30
  text "179" at 2294.83,108.55 h30
  text "COMPONENTS MARKED 'DNP' SHOULD NOT BE POPULATED." at 493.5,-1419.5 h30
  text "ASSEMBLY VARIANT:" at 493,-1535 h30
  text ".VariantName" at 1529,-1535 h30
  text "ALL ARTWORK VIEWED FROM TOP SIDE" at -888.5,-1756.67 h30
  text "BOARD #:" at 1588,-1756.67 h30
  text ".PRJ_Number" at 2133.5,-1756.67 h30
  text "REV:" at 2978,-1756.67 h30
  text ".PCB_Rev" at 3269.5,-1756.67 h30
  text "SVN REV:" at 3816,-1756.67 h30
  text ".VersionControl_RevNumber" at 4322,-1756.67 h30
  text ".layer_Name" at -125,-1939 h30
  text "LAYER NAME =" at -895,-1946 h30
  text ".plot_File_Name" at -897,-2135 h30
  text "GENERATED    :" at 1590,-2165.34 h30
  text ".Print_Date" at 2459.5,-2165.34 h30
  text ".Print_Time" at 3188.5,-2165.34 h30
  text "TEXAS INSTRUMENTS" at 4453,-2165.34 h30
M6 Assembly Bottom:
  lines w10: -952.5,-1828.33 5649.5,-1828.33 ; -950.5,-2031.67 5649.5,-2031.67 ; 1077.5,-1828.33 1077.5,-1625 ; 1917.5,-1828.33 1917.5,-1625 ; 3184.5,-2235 3184.5,-1625 ; 4073.5,-2235 5649,-2235 5649,-1625 -952.5,-1625 -952.5,-2235 1644.5,-2235 5649.5,-2235 5649.5,-1625
  text "COMPONENTS MARKED 'DNP' SHOULD NOT BE POPULATED." at 5442,-1419 h30
  text ".VariantName" at 4398,-1535 h30
  text "ASSEMBLY VARIANT:" at 5437,-1535 h30
  text "SVN REV:" at 881.5,-1757.17 h30
  text ".PCB_Rev" at 1428,-1757.17 h30
  text "REV:" at 1719.5,-1757.17 h30
  text ".PRJ_Number" at 2564,-1757.17 h30
  text "BOARD #:" at 3109.5,-1757.17 h30
  text "PCB VIEWED FROM BOTTOM SIDE" at 5586,-1757.17 h30
  text "LAYER NAME =" at 5581,-1942 h30
  text ".Layer_Name" at 4808,-1949 h30
  text "IGNORE ->" at 1887.85,-1959.49 h30
  text ".Print_Time" at 1509,-2165.84 h30
  text ".Print_Date" at 2238,-2165.84 h30
  text "GENERATED    :" at 3107.5,-2165.84 h30
  text ".plot_File_Name" at 4780.5,-2165.84 h30
  text "PLOT NAME =" at 5586,-2165.84 h30
M9 Title Sheet:
  drawing of 57 lines, arcs and shapes, not listed
  text "1" at 79.84,6935.5 h70
  text "2" at 2575.5,6935.5 h70
  text "3" at 5064.84,6935.5 h70
  text "4" at 7571.51,6935.5 h70
  text "5" at 10070.5,6935.5 h70
  text "6" at 12575.5,6935.5 h70
  text "A" at -1076.5,5792.5 h70
  text "A" at 13723.5,5792.5 h70
  text "B" at -1076.5,3412.5 h70
  text "B" at 13723.5,3412.5 h70
  text "C" at -1076.5,1037.5 h70
  text "C" at 13723.5,1037.5 h70
  text "PROJECT TITLE:" at 10683.5,-823.5 h45
  text ".PRJ_Title" at 10660,-950 h70
  text "DESIGNED FOR:" at 10683.5,-1124.5 h45
  text ".PRJ_Customer" at 10733.5,-1264.5 h70
  text "D" at -1076.5,-1332.5 h70
  text "D" at 13723.5,-1332.5 h70
  text "FILE NAME:" at 10683.5,-1424.5 h45
  text ".PCB_File_Name_No_Path" at 10733.5,-1544.5 h70
  text "Texas Instruments (TI) and/or its licensors do not warrant the accuracy or completeness of this specification" at 5714,-1706.34 h45
  text "ENGINEER:" at 10683.5,-1714.5 h45
  text "LAYOUT BY:" at 12188.5,-1714.5 h45
  text "or any information contained therein. TI and/or its licensors do not warrant that this design will meet" at 5669.01,-1819 h45
  text ".PRJ_Engineer" at 10733.5,-1869.49 h70
  text ".PCB_Layout" at 12239,-1869.49 h70
  text "the specifications, will be suitable for your application or fit for any particular purpose, or will operate in" at 5669.01,-1931.67 h45
  text "ALTIUM DESIGNER VERSION:" at 12188.5,-2024.5 h45
  text "an implementation. TI and/or its licensors do not warrant that the design is production worthy. You should" at 5669.01,-2044.33 h45
  text "completely validate and test your design implementation to confirm the system functionality for your application." at 5714,-2157 h45
  text ".print_Scale" at 10733.5,-2157.83 h70
  text ".Application_BuildNumber" at 12239,-2157.83 h70
  text "2" at 2575.5,-2364.5 h70
  text "3" at 5064.84,-2364.5 h70
  text "4" at 7571.51,-2364.5 h70
  text "5" at 10070.5,-2364.5 h70
  text "6" at 12575.5,-2364.5 h70
M10 Fab Notes:
  drawing of 228 lines, arcs and shapes, not listed
  text "DESIGN INFORMATION" at 11721.02,5709 h60
  text "(REFER ALSO ARRAY/PANEL PROFILING INFORMATION)" at 11359.46,5547.29 h60
  text "BOARD SIZE" at 10673.46,5543 h60
  text "3345MIL" at 11135.78,5415.18 h60
  text "X" at 11641.46,5415.18 h60
  text "4425MIL" at 11872.78,5415.18 h60
  text "Number of Layers :" at 11076.46,5218 h60
  text "4" at 12171.27,5208 h60
  text "MIN. TRACK WIDTH:" at 11076.46,5079 h60
  text "8" at 12172.7,5079 h60
  text "MIL" at 12327.46,5079 h60
  text "MIN. CLEARANCE:" at 11076.46,4947 h60
  text "MIL" at 12327.46,4947 h60
  text "7.8" at 12133,4944 h60
  text "MIN. VIA DRILL SIZE:" at 11076.46,4815 h60
  text "MIL" at 12327.46,4815 h60
  text "7.874" at 12040,4809 h60
  text "5.90 MIL" at 11771.46,4673.29 h60
  text "MINIMUM ANNULAR RING" at 10747.23,4669 h60
  text "EXTERNAL" at 12479.46,4669 h60
  text "PER" at 10947.23,4551 h60
  text "IPC-D-275 CLASS 2 LEVEL C" at 11167.23,4551 h60
  text "MIL, HOLES" at 12655.46,4438.71 h60
  text "+/-" at 12263,4438 h60
  text "+/-" at 13117,4438 h60
  text "REGISTRATION TOLERANCES:" at 10747.23,4433 h60
  text "METAL" at 11947,4433 h60
  text "5" at 12523.2,4433 h60
  text "3" at 13356.2,4433 h60
  text "MIL" at 13472.46,4433 h60
  text "MATERIAL:" at 10672.46,4223.54 h60
  text "FR-4 High Tg" at 11658.9,4083.21 h60
  text "X" at 10939,4078 h60
  text "FR-408" at 11093.46,4074.64 h60
  text "OTHER" at 12581.46,4074.64 h60
  text "63 MIL (1.6mm) +/-10%" at 11413.56,3911.92 h60
  text "THICKNESS:" at 10747.23,3907.64 h60
  text "X" at 11285.4,3907.64 h60
  text "OTHER" at 12698.46,3907.64 h60
  text "TOLERANCE:" at 10747.23,3749.64 h60
  text "X" at 11586.53,3749.64 h60
  text "ANSI IPC-6012 TYPE 3 CLASS 2" at 11773.48,3749.64 h60
  text "OTHER +/-" at 11773.46,3593.64 h60
  text "BOW & TWIST:" at 10747.23,3436.64 h60
  text "X" at 11586.53,3436.64 h60
  text "ANSI IPC-6012 TYPE 3 CLASS 2" at 11773.48,3436.64 h60
  text "OTHER +/-" at 11773.46,3278.13 h60
  text "COPPER THICKNESS (FINISHED):" at 10672.46,3142.64 h60
  text "1.4MIL (1oz)" at 11552.46,2989.92 h60
  text "2MIL (1.4oz)" at 12319.46,2989.92 h60
  text "2.8MIL (2oz)" at 13046.46,2989.92 h60
  text "OUTER:" at 11029.46,2985.64 h60
  text "X" at 11424,2985 h60
  text "1.4MIL (1oz)" at 11552.46,2832.92 h60
  text "2.8MIL (2oz)" at 12319.46,2832.92 h60
  text "N/A" at 13046,2833.29 h60
  text "INNER SIGNAL:" at 10740.38,2828.64 h60
  text "X" at 11419,2826 h60
  text "DRILLING:" at 10672.46,2689.64 h60
  text "REFERENCE:" at 10747.23,2572.64 h60
  text "X" at 11395.46,2572.64 h60
  text "AS SHOWN" at 11582.46,2572.64 h60
  text "X" at 12296.46,2572.64 h60
  text "NC_DRILL FILES" at 12433.46,2572.64 h60
  text "PTH MIN COPPER THICKNESS:" at 10747.23,2414.64 h60
  text "X" at 12097.46,2414.64 h60
  text "1MIL" at 12234.46,2414.64 h60
  text "OTHER" at 12731.46,2414.64 h60
  text "BOARD FINISH:" at 10672.46,2255.64 h60
  text "SILKSCREEN:" at 10827.68,2137.64 h60
  text "X" at 11776.46,2137.64 h60
  text "TOP" at 11902.46,2137.64 h60
  text "X" at 12286.46,2137.64 h60
  text "BOTTOM" at 12413.46,2137.64 h60
  text "SILKSCREEN COLOR:" at 10827.68,1970.64 h60
  text "X" at 11775.42,1970.64 h60
  text "WHITE" at 11902.46,1970.64 h60
  text "OTHER" at 12413.46,1970.64 h60
  text "SOLDER RESIST COLOR:" at 10827.68,1800.64 h60
  text "X" at 11395.42,1641.44 h60
  text "GREEN" at 11522.46,1641.44 h60
  text "BLUE" at 12113.46,1641.44 h60
  text "OTHER" at 12651.46,1641.44 h60
  text "IMMERSION GOLD (ENIG)" at 11733.46,1452.92 h60
  text "ENEPIG" at 13071,1449.64 h60
  text "SURFACE FINISH:" at 10672.46,1448.64 h60
  text "X" at 11546.51,1448.64 h60
  text "IMM. TIN/SILVER OR EQUIV" at 11002,1291.64 h60
  text "OTHER" at 12433.46,1291.64 h60
  text "ARRAY/PANEL:" at 10672.46,1112.64 h60
  text "CUT AND TRIM PER MECH LAYER 1" at 11733.46,1108.35 h60
  text "N.C. ROUTE" at 11733.46,956.64 h60
  text "X" at 12412.46,956.64 h60
  text "V. SCORE" at 12599.46,956.64 h60
  text "CERTIFICATION:" at 10672.46,819.64 h60
  text "MATERIALS AND WORKMANSHIP FOR ALL PCBS" at 11397.46,819.64 h60
  text "TO MEET OR EXCEED THE REQUIREMENTS OF:" at 11397.46,721.64 h60
  text "X" at 11023.96,585.13 h60
  text "ANSI IPC-A-600F CLASS ->" at 11162.96,585.13 h60
  text "X" at 12802.02,585.13 h60
  text "2" at 12920.96,585.14 h60
  text "1" at 12605.96,583.64 h60
  text "3" at 13274.96,583.64 h60
  text "X" at 11026.02,425.64 h60
  text "UL 94V-0" at 11162.96,425.64 h60
  text "X" at 11838.02,425.64 h60
  text "RoHS" at 11974.96,425.64 h60
  text "OTHER" at 12619.36,425.64 h60
  text "PER ORDER" at 13016.42,425.64 h60
  text "VIA TENTING:" at 11890,292 h60
  text "X" at 12972.02,289.13 h60
  text "ADDITIONAL REQUIREMENTS:" at 10672.46,284.64 h60
  text "YES" at 12439.67,282.92 h60
  text "NO" at 12804.47,277.69 h60
  text "MICROSECTION:" at 10747.23,169.64 h60
  text "YES" at 11652.96,169.64 h60
  text "IMPEDANCE CONTROL:" at 11912,163 h60
  text "YES" at 12896,162 h60
  text "X" at 13438,155 h60
  text "NO" at 13271.47,144.69 h60
  text "REQUIRED" at 12514.46,13.49 h60
  text "BARE BOARD ELEC. TEST:" at 10747.23,10.64 h60
  text "NONE" at 12052.96,10.64 h60
  text "X" at 12387.46,10.64 h60
  text "PER ORDER" at 13106.46,10.64 h60
  text "MANUFACTURER'S UL:" at 10747.23,-146.36 h60
  text "RAIL" at 11912.96,-150.65 h60
  text "METAL" at 12404.77,-150.65 h60
  text "X" at 12780,-151 h60
  text "SILK" at 12916.46,-150.65 h60
M11 Gerber Information:
  lines w10: -952,-2031.17 5648,-2031.17 ; -952,-1827.83 5650,-1827.83 ; -952,-1624.5 -952,-2234.5 3053,-2234.5 5650,-2234.5 5650,-1624.5 -951.5,-1624.5 -951.5,-2234.5 ; 1513,-2234.5 1513,-1624.5 ; 2780,-1827.83 2780,-1624.5 ; 3620,-1827.83 3620,-1624.5 ; 4242,-2241 4242,-2038.17
  text "BOARD #:" at 1588,-1756.67 h60
  text ".PRJ_Number" at 2133.5,-1756.67 h60
  text "REV:" at 2978,-1756.67 h60
  text ".PCB_Rev" at 3269.5,-1756.67 h60
  text "SVN REV:" at 3816,-1756.67 h60
  text ".VersionControl_RevNumber" at 4322,-1756.67 h60
  text "ALL ARTWORK VIEWED FROM TOP SIDE" at -889.5,-1762.67 h60
  text "LAYER NAME =" at -891,-1946 h60
  text ".plot_File_Name" at -899,-2145 h60
  text "GENERATED    :" at 1590,-2165.34 h60
  text ".Print_Date" at 2459.5,-2165.34 h60
  text ".Print_Time" at 3188.5,-2165.34 h60
  text "TEXAS INSTRUMENTS" at 4453,-2165.34 h60
M12 Stackup:
  lines w6: 10700,6359 13250,6359 ; 10700,6463.4 13250,6463.4 ; 10640,5874 ccw(c10674,5874) 10674,5840 13276,5840 ccw(c13276,5874) 13310,5874 13310,6580 ccw(c13276,6580) 13276,6614 10674,6614 ccw(c10674,6580) 10640,6580 10640,5874
  text "Layer Stack Up Detail for: TIDA-00316_E2" at 10700,6496.1 h57
  text "Layer" at 10700,6424.4 h24
  text "Gerber" at 11595.81,6424.4 h24
  text "Copper" at 12159.33,6424.4 h24
  text "Dielectric" at 12762.04,6424.4 h24
  text "Name" at 10700,6376.4 h24
  text "Document" at 11595.81,6376.4 h24
  text "Thickness" at 12159.33,6376.4 h24
  text "Material" at 12762.04,6376.4 h24
  text "Top Solder Mask" at 10700,6283.44 h34
  text "(.GTS)" at 11595.81,6283.44 h34
  text "Solder Resist" at 12762.04,6283.44 h34
  text "Top Layer" at 10700,6186.69 h34
  text "(.GTL)" at 11595.81,6186.69 h34
  text "1.4mil" at 12159.33,6186.69 h34
  text "FR408" at 12791,6186 h34
  text "FR408" at 12790,6121 h34
  text "(.G1)" at 11599.81,6119.69 h34
  text "1.4mil" at 12160.33,6115.69 h34
  text "L1_GND" at 10704,6113 h34
  text "FR408" at 12791,6056 h34
  text "1.4mil" at 12163.33,6049.69 h34
  text "(.G2)" at 11599.81,6046.69 h34
  text "L1_POWER" at 10705,6037 h34
  text "FR408" at 12793,5967 h34
  text "Bottom Layer" at 10706,5957 h34
  text "(.GBL)" at 11604,5956 h34
  text "1.4mil" at 12164,5950 h34
  text "Solder Resist" at 12756,5883 h34
  text "(.GBS)" at 11601,5876 h34
  text "Bottom Solder Mask" at 10703,5871 h34
M13 Component Bodies Top:
  text ".Layer_Name" at -83,-1959.49 h60
M14 Component Bodies Bottom:
  text ".Layer_Name" at -83,-1959.49 h60
M15 Courtyards Top:
  text ".Layer_Name" at -83,-1959.49 h60
M16 Courtyards Bottom:
  text ".Layer_Name" at -83,-1959.49 h60
Drill Drawing:
  text ".legend" at 5334,280 h60
  text "Drill Table" at 5331,109 h60
  text "FOR 7.874MIL DRILL +0/-7.874MIL" at 5360,-98 h60
  text "FOR 12MIL DRILL +0/-12MIL" at 5357,-201 h60
  text "FOR 16MIL DRILL +0/-16MIL" at 5358,-305 h60
  text "FOR PTH DRILL +/-3MIL" at 5358,-423 h60
  text "FOR NPTH DRILL +/-2MIL" at 5364,-529 h60
  text ".layer_Name" at 22,-1943 h60

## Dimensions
0,0 to 0,4425 on M2 Board Dimensions
0,4425 to 3345,4425 on M2 Board Dimensions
